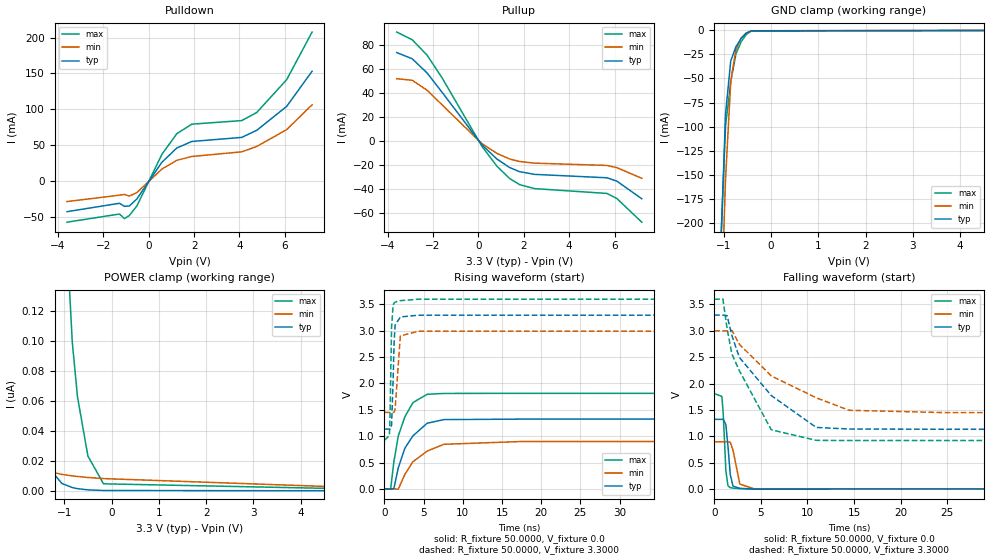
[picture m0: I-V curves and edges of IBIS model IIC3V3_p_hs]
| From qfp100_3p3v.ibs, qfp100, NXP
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[Model] IIC3V3_p_hs
|   Model IIC3V3_p_hs
| This model was characterised for following simulation conditions:
| External (pad) voltage:
|   - Typ: 3.3V,   - Min: 3.0V,   - Max: 3.6V
| Library cells for typ/min/max conditions are connected as defined below:
|  IO - External Pad
|  A - Core Input
|  EN - Output Buffer Enable
|  BOOST - vdde
|  EGP - vdd
|  EHS - vdd
|  ENZI - vdd
|  EPD - gnd
|  EPUN - vdd
|  ZI - NC
|  ZIF - NC
|  gnd - gnd
|  gnde - gnde
|  vdd - vdd
|  vdde - vdde
| All other pins connected to ground
Model_type I/O
Polarity   Non-Inverting
Enable   Active-Low
Vinl =   0.9900V
Vinh =   2.3100V
Vmeas =  1.6500V
Cref =   0.0F
Rref =   1.0000k
Vref =   0.0V
C_comp   3.6227pF   3.4779pF   3.7656pF
|C_comp_pullup   0.9287pF   0.9115pF   0.9356pF
|C_comp_pulldown   2.3426pF   2.4945pF   2.1982pF
[Model Spec]
| variable   typ   min   max
Vinh   0.9900V   0.9000V   1.0800V
Vinl   2.3100V   2.1000V   2.5200V
Vmeas   1.6500V   1.5000V   1.8000V
[Temperature Range]   25.0000   0.1250k   -40.0000
[Voltage Range]   3.3000V   3.0000V   3.6000V
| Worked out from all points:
|   slope of the pulldown table from 0 to 0.495 V, typ, clamps not added: 22 ohm
|   slope of the pullup table from 0 to 0.495 V, typ, clamps not added: 50.2 ohm
|   GND clamp passes 1 mA (typ) near -0.43 V on its own axis
|   rising waveform, R_fixture 50.0000, V_fixture 0.0: 20-80 % time 2.42ns typ, 3.15ns min, 1.81ns max; typ from 0 V to 1.32 V
|   rising waveform, R_fixture 50.0000, V_fixture 3.3000: 20-80 % time 230ps typ, 322ps min, 186ps max; typ from 1.14 V to 3.3 V
|   falling waveform, R_fixture 50.0000, V_fixture 0.0: 20-80 % time 371ps typ, 535ps min, 282ps max; typ from 1.32 V to 0 V
|   falling waveform, R_fixture 50.0000, V_fixture 3.3000: 20-80 % time 5.52ns typ, 7.85ns min, 3.84ns max; typ from 3.3 V to 1.14 V
[Pulldown]
|Voltage   I(typ)   I(min)   I(max)
-3.6V     -43.22mA   -29.09mA   -57.9mA
-1.29V    -31.46mA   -20.15mA   -46.47mA
-1.07V    -35.79mA   -19.19mA   -52.9mA
-850mV    -35.14mA   -21.36mA   -48.43mA
-520mV    -25.35mA   -16.52mA   -35.11mA
580mV     25.81mA    16.3mA     36.8mA
1.24V     45.79mA    28.53mA    65.82mA
1.9V      54.89mA    33.9mA     79.08mA
4.1V      60.56mA    40.39mA    84.05mA
4.76V     70.46mA    47.89mA    95.34mA
6.08V     103.9mA    71.43mA    141.2mA
7.2V      153mA      106.1mA    207.7mA
[Pullup]
|Voltage   I(typ)   I(min)   I(max)
-3.6V     73.7mA     51.87mA    90.79mA
-2.92V    68.56mA    50.58mA    84.45mA
-2.26V    56.64mA    42.24mA    71.49mA
-1.6V     40.55mA    30.05mA    52.55mA
160mV     -3.402mA   -2.371mA   -4.704mA
820mV     -15.2mA    -10.46mA   -21.22mA
1.37V     -22.16mA   -15.02mA   -31.28mA
1.81V     -25.65mA   -17.18mA   -36.45mA
2.47V     -27.92mA   -18.56mA   -39.79mA
5.66V     -30.76mA   -20.47mA   -43.83mA
6.1V      -33.55mA   -22.29mA   -48.04mA
7.2V      -48.27mA   -31.2mA    -67.82mA
[GND_clamp]
|Voltage   I(typ)   I(min)   I(max)
-3.6V     -5.602A    -5.487A    -5.717A
-1.07V    -242mA     -316.8mA   -230.5mA
-960mV    -86.75mA   -154.7mA   -99.48mA
-850mV    -31.81mA   -53.08mA   -53.5mA
-740mV    -16.96mA   -19.87mA   -24.43mA
-630mV    -8.589mA   -7.919mA   -11.88mA
-520mV    -2.996mA   -2.727mA   -4.187mA
-410mV    -432.5uA   -495.8uA   -580.8uA
7.2V      0A         0A         0A
[POWER_clamp]
|Voltage   I(typ)   I(min)   I(max)
-3.6V     2.12uA     118.8nA    63.41uA
-3.03V    844.5nA    61.84nA    27.62uA
-2.37V    225.8nA    29.91nA    8.403uA
-2.04V    102.5nA    21.72nA    4.105uA
-1.82V    57.11nA    17.98nA    2.406uA
-1.49V    21.61nA    14.11nA    975.4nA
-1.05V    4.967nA    11.05nA    231.3nA
-830mV    2.261nA    10.06nA    99.54nA
-720mV    1.525nA    9.658nA    63.01nA
-500mV    718.9pA    8.985nA    23.37nA
-170mV    294.4pA    8.237nA    4.755nA
7.2V      0A         0A         0A
[Ramp]
| variable   typ   min   max
dV/dt_r  0.7941/2.4211n   0.5390/3.1525n   1.0875/1.8120n
dV/dt_f  1.2989/5.5187n   0.9297/7.8507n   1.6070/3.8381n
R_load = 50.0000
[Rising Waveform]
R_fixture= 50.0000
V_fixture= 0.0
V_fixture_min= 0.0
V_fixture_max= 0.0
|time   V(typ)   V(min)   V(max)
0s        2.243nV    52.63nV    27.54nV
783.4ps   -2.546mV   48.23uV    -3.663mV
1.2ns     6.371mV    -1.183mV   516.9mV
1.762ns   400.2mV    -5.572mV   1.005V
2.604ns   772.3mV    274.8mV    1.368V
3.633ns   1.006V     515.9mV    1.636V
5.446ns   1.245V     716.8mV    1.794V
7.589ns   1.314V     845.6mV    1.81V
17.45ns   1.323V     898mV      1.812V
1us       1.323V     898.3mV    1.813V
[Rising Waveform]
R_fixture= 50.0000
V_fixture= 3.3000
V_fixture_min= 3.0000
V_fixture_max= 3.6000
|time   V(typ)   V(min)   V(max)
0s        1.135V     1.45V      921.7mV
627.3ps   1.135V     1.45V      1.012V
700.7ps   1.134V     1.451V     1.326V
903.6ps   1.208V     1.45V      3.068V
1.101ns   2.057V     1.448V     3.484V
1.223ns   2.763V     1.454V     3.525V
1.356ns   3.105V     1.506V     3.542V
2.023ns   3.26V      2.9V       3.57V
4.301ns   3.294V     2.99V      3.597V
1us       3.3V       3V         3.6V
[Falling Waveform]
R_fixture= 50.0000
V_fixture= 0.0
V_fixture_min= 0.0
V_fixture_max= 0.0
|time   V(typ)   V(min)   V(max)
0s        1.323V     898.3mV    1.813V
822ps     1.323V     898.3mV    1.758V
972.4ps   1.326V     898.3mV    1.431V
1.252ns   1.222V     898.1mV    350.6mV
1.476ns   816.9mV    900.3mV    64.93mV
1.726ns   277.3mV    889.4mV    27.64mV
2.019ns   57.27mV    737.3mV    19.74mV
2.754ns   14.85mV    95.71mV    10.98mV
4.273ns   3.379mV    7.479mV    1.748mV
1us       13.95nV    73.04nV    34.74nV
[Falling Waveform]
R_fixture= 50.0000
V_fixture= 3.3000
V_fixture_min= 3.0000
V_fixture_max= 3.6000
|time   V(typ)   V(min)   V(max)
0s        3.3V       3V         3.6V
933.7ps   3.299V     3V         3.603V
1.389ns   3.287V     2.999V     3.037V
1.891ns   2.917V     3.01V      2.567V
2.697ns   2.498V     2.747V     2.246V
6.123ns   1.774V     2.146V     1.125V
10.95ns   1.17V      1.732V     925.1mV
14.46ns   1.14V      1.495V     922mV
24.74ns   1.135V     1.451V     921.7mV
1us       1.135V     1.45V      921.7mV
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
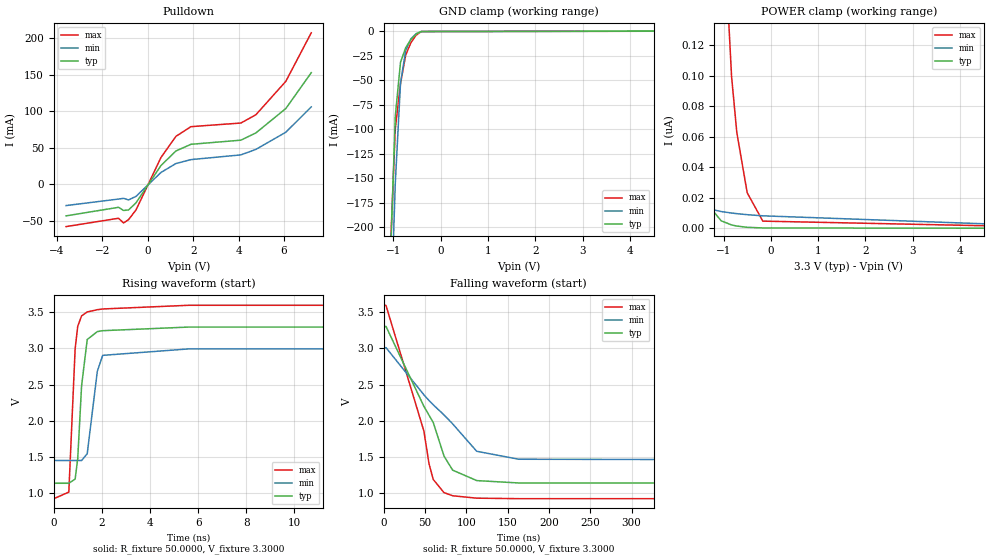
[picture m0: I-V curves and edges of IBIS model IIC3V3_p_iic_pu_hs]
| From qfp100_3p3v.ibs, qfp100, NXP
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[Model] IIC3V3_p_iic_pu_hs
|   Model IIC3V3_p_iic_pu_hs
| This model was characterised for following simulation conditions:
| External (pad) voltage:
|   - Typ: 3.3V,   - Min: 3.0V,   - Max: 3.6V
| Library cells for typ/min/max conditions are connected as defined below:
|  IO - External Pad
|  A - Core Input
|  EN - Output Buffer Enable
|  BOOST - vdde
|  ECS - vdd
|  EGP - gnd
|  ENZI - vdd
|  EPD - gnd
|  EPUN - vdd
|  SSEL - vdd
|  ZI - NC
|  ZIF - NC
|  gnd - gnd
|  gnde - gnde
|  vdd - vdd
|  vdde - vdde
| All other pins connected to ground
Model_type I/O_open_drain
Polarity   Non-Inverting
Enable   Active-Low
Vinl =   0.9900V
Vinh =   2.3100V
Vmeas =  1.6500V
Cref =   0.0F
Rref =   1.0000k
Vref =   3.3000V
C_comp   3.6227pF   3.4779pF   3.7656pF
|C_comp_pullup   0.9287pF   0.9114pF   0.9356pF
|C_comp_pulldown   2.3426pF   2.4946pF   2.1982pF
[Model Spec]
| variable   typ   min   max
Vinh   0.9900V   0.9000V   1.0800V
Vinl   2.3100V   2.1000V   2.5200V
Vmeas   1.6500V   1.5000V   1.8000V
Vref   3.3000V   3.0000V   3.6000V
Cref   0.0F   0.0F   0.0F
Rref   1.0000k   1.0000k   1.0000k
[Temperature Range]   25.0000   0.1250k   -40.0000
[Voltage Range]   3.3000V   3.0000V   3.6000V
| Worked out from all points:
|   slope of the pulldown table from 0 to 0.495 V, typ, clamps not added: 22 ohm
|   GND clamp passes 1 mA (typ) near -0.43 V on its own axis
|   rising waveform, R_fixture 50.0000, V_fixture 3.3000: 20-80 % time 227ps typ, 309ps min, 192ps max; typ from 1.14 V to 3.3 V
|   falling waveform, R_fixture 50.0000, V_fixture 3.3000: 20-80 % time 50.8ns typ, 68.7ns min, 38.5ns max; typ from 3.3 V to 1.14 V
[Pulldown]
|Voltage   I(typ)   I(min)   I(max)
-3.6V     -43.22mA   -29.09mA   -57.9mA
-1.29V    -31.46mA   -20.15mA   -46.47mA
-1.07V    -35.79mA   -19.19mA   -52.9mA
-850mV    -35.14mA   -21.36mA   -48.43mA
-520mV    -25.35mA   -16.52mA   -35.11mA
580mV     25.81mA    16.3mA     36.8mA
1.24V     45.79mA    28.53mA    65.82mA
1.9V      54.89mA    33.9mA     79.08mA
4.1V      60.56mA    40.39mA    84.05mA
4.76V     70.46mA    47.89mA    95.34mA
6.08V     103.9mA    71.43mA    141.2mA
7.2V      153mA      106.1mA    207.7mA
[GND_clamp]
|Voltage   I(typ)   I(min)   I(max)
-3.6V     -5.602A    -5.487A    -5.717A
-1.07V    -242mA     -316.8mA   -230.5mA
-960mV    -86.75mA   -154.7mA   -99.48mA
-850mV    -31.81mA   -53.08mA   -53.5mA
-740mV    -16.96mA   -19.87mA   -24.43mA
-630mV    -8.589mA   -7.919mA   -11.88mA
-520mV    -2.996mA   -2.727mA   -4.187mA
-410mV    -432.5uA   -495.8uA   -580.8uA
7.2V      0A         0A         0A
[POWER_clamp]
|Voltage   I(typ)   I(min)   I(max)
-3.6V     2.12uA     118.8nA    63.41uA
-3.03V    844.5nA    61.84nA    27.62uA
-2.37V    225.8nA    29.91nA    8.403uA
-2.04V    102.5nA    21.72nA    4.105uA
-1.82V    57.11nA    17.98nA    2.406uA
-1.49V    21.61nA    14.11nA    975.4nA
-1.05V    4.967nA    11.05nA    231.3nA
-830mV    2.261nA    10.06nA    99.54nA
-720mV    1.525nA    9.658nA    63.01nA
-500mV    718.9pA    8.985nA    23.37nA
-170mV    294.4pA    8.237nA    4.755nA
7.2V      0A         0A         0A
[Ramp]
| variable   typ   min   max
dV/dt_r  1.2989/0.2271n   0.9297/0.3090n   1.6070/0.1925n
dV/dt_f  1.2989/50.7796n   0.9297/68.6526n   1.6070/38.5019n
R_load = 50.0000
[Rising Waveform]
R_fixture= 50.0000
V_fixture= 3.3000
V_fixture_min= 3.0000
V_fixture_max= 3.6000
|time   V(typ)   V(min)   V(max)
0s        1.135V     1.45V      921.7mV
623.4ps   1.135V     1.45V      1.013V
886ps     1.193V     1.45V      2.995V
994ps     1.479V     1.45V      3.305V
1.153ns   2.48V      1.449V     3.448V
1.388ns   3.122V     1.544V     3.503V
1.807ns   3.231V     2.682V     3.534V
2.03ns    3.244V     2.903V     3.544V
5.603ns   3.294V     2.992V     3.595V
1us       3.3V       3V         3.6V
[Falling Waveform]
R_fixture= 50.0000
V_fixture= 3.3000
V_fixture_min= 3.0000
V_fixture_max= 3.6000
|time   V(typ)   V(min)   V(max)
0s        3.3V       3V         3.6V
2.46ns    3.303V     3.01V      3.593V
48.38ns   2.199V     2.358V     1.857V
54.58ns   2.076V     2.28V      1.407V
59.71ns   1.976V     2.22V      1.188V
72.76ns   1.512V     2.08V      1.006V
83.18ns   1.317V     1.957V     962.6mV
112.4ns   1.172V     1.577V     928.9mV
163.4ns   1.139V     1.467V     922.1mV
1us       1.135V     1.45V      921.7mV
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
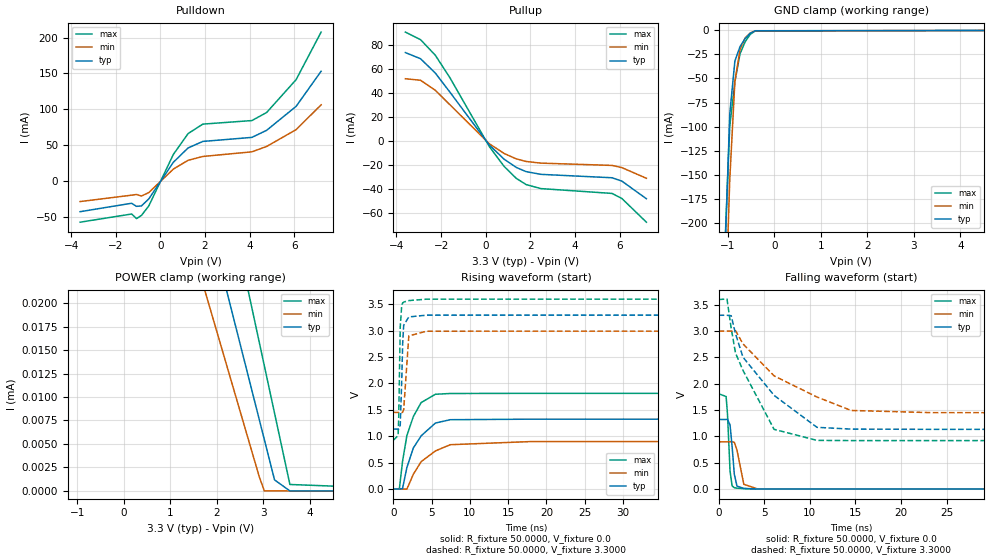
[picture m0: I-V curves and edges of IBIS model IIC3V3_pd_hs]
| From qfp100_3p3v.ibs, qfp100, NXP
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[Model] IIC3V3_pd_hs
|   Model IIC3V3_pd_hs
| This model was characterised for following simulation conditions:
| External (pad) voltage:
|   - Typ: 3.3V,   - Min: 3.0V,   - Max: 3.6V
| Library cells for typ/min/max conditions are connected as defined below:
|  IO - External Pad
|  A - Core Input
|  EN - Output Buffer Enable
|  BOOST - vdde
|  EGP - vdd
|  EHS - vdd
|  ENZI - vdd
|  EPD - vdd
|  EPUN - vdd
|  ZI - NC
|  ZIF - NC
|  gnd - gnd
|  gnde - gnde
|  vdd - vdd
|  vdde - vdde
| All other pins connected to ground
Model_type I/O
Polarity   Non-Inverting
Enable   Active-Low
Vinl =   0.9900V
Vinh =   2.3100V
Vmeas =  1.6500V
Cref =   0.0F
Rref =   1.0000k
Vref =   0.0V
C_comp   3.5907pF   3.4406pF   3.7387pF
|C_comp_pullup   0.9138pF   0.9000pF   0.9174pF
|C_comp_pulldown   2.3267pF   2.4802pF   2.1806pF
[Model Spec]
| variable   typ   min   max
Vinh   0.9900V   0.9000V   1.0800V
Vinl   2.3100V   2.1000V   2.5200V
Vmeas   1.6500V   1.5000V   1.8000V
[Temperature Range]   25.0000   0.1250k   -40.0000
[Voltage Range]   3.3000V   3.0000V   3.6000V
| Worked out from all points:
|   slope of the pulldown table from 0 to 0.495 V, typ, clamps not added: 22 ohm
|   slope of the pullup table from 0 to 0.495 V, typ, clamps not added: 50.2 ohm
|   GND clamp passes 1 mA (typ) near -0.43 V on its own axis
|   rising waveform, R_fixture 50.0000, V_fixture 0.0: 20-80 % time 2.41ns typ, 3.15ns min, 1.81ns max; typ from 0 V to 1.32 V
|   rising waveform, R_fixture 50.0000, V_fixture 3.3000: 20-80 % time 230ps typ, 322ps min, 186ps max; typ from 1.14 V to 3.3 V
|   falling waveform, R_fixture 50.0000, V_fixture 0.0: 20-80 % time 371ps typ, 533ps min, 281ps max; typ from 1.32 V to 0 V
|   falling waveform, R_fixture 50.0000, V_fixture 3.3000: 20-80 % time 5.51ns typ, 7.83ns min, 3.82ns max; typ from 3.3 V to 1.14 V
[Pulldown]
|Voltage   I(typ)   I(min)   I(max)
-3.6V     -43.22mA   -29.09mA   -57.9mA
-1.29V    -31.46mA   -20.15mA   -46.47mA
-1.07V    -35.79mA   -19.19mA   -52.9mA
-850mV    -35.14mA   -21.36mA   -48.43mA
-520mV    -25.35mA   -16.52mA   -35.11mA
580mV     25.81mA    16.3mA     36.8mA
1.24V     45.79mA    28.53mA    65.82mA
1.9V      54.89mA    33.9mA     79.08mA
4.1V      60.55mA    40.38mA    84.05mA
4.76V     70.44mA    47.87mA    95.32mA
6.08V     103.9mA    71.39mA    141.2mA
7.2V      152.9mA    106mA      207.6mA
[Pullup]
|Voltage   I(typ)   I(min)   I(max)
-3.6V     73.65mA    51.83mA    90.73mA
-2.92V    68.52mA    50.55mA    84.41mA
-2.26V    56.61mA    42.22mA    71.46mA
-1.6V     40.53mA    30.04mA    52.53mA
160mV     -3.403mA   -2.371mA   -4.704mA
820mV     -15.2mA    -10.46mA   -21.22mA
1.37V     -22.16mA   -15.02mA   -31.28mA
1.81V     -25.65mA   -17.18mA   -36.45mA
2.47V     -27.92mA   -18.56mA   -39.79mA
5.66V     -30.76mA   -20.47mA   -43.83mA
6.1V      -33.55mA   -22.29mA   -48.04mA
7.2V      -48.27mA   -31.2mA    -67.82mA
[GND_clamp]
|Voltage   I(typ)   I(min)   I(max)
-3.6V     -5.602A    -5.487A    -5.717A
-1.07V    -242mA     -316.8mA   -230.5mA
-960mV    -86.76mA   -154.7mA   -99.49mA
-850mV    -31.82mA   -53.09mA   -53.51mA
-740mV    -16.97mA   -19.87mA   -24.44mA
-630mV    -8.597mA   -7.926mA   -11.89mA
-520mV    -3.004mA   -2.733mA   -4.196mA
-410mV    -439.7uA   -501.8uA   -589.4uA
7.2V      0A         0A         0A
[POWER_clamp]
|Voltage   I(typ)   I(min)   I(max)
-3.6V     137uA      111.9uA    228.9uA
-3.47V    134.1uA    109.7uA    215.6uA
-3.25V    129.3uA    106uA      196.2uA
-2.92V    122.3uA    100.4uA    172.9uA
-2.48V    113.3uA    92.88uA    150.2uA
-2.04V    104.5uA    85.42uA    133.7uA
-1.16V    87.2uA     70.51uA    109.7uA
2.91V     7.626uA    1.527uA    15.86uA
3.02V     5.475uA    0A         13.33uA
3.24V     1.173uA    0A         8.273uA
3.57V     0A         0A         687.1nA
7.2V      0A         0A         0A
[Ramp]
| variable   typ   min   max
dV/dt_r  0.7935/2.4144n   0.5386/3.1478n   1.0867/1.8089n
dV/dt_f  1.2983/5.5124n   0.9293/7.8350n   1.6062/3.8243n
R_load = 50.0000
[Rising Waveform]
R_fixture= 50.0000
V_fixture= 0.0
V_fixture_min= 0.0
V_fixture_max= 0.0
|time   V(typ)   V(min)   V(max)
0s        2.145nV    50.58nV    26.14nV
784.7ps   -2.611mV   49.1uV     -3.137mV
1.202ns   7.028mV    -1.221mV   519mV
1.771ns   405.7mV    -4.318mV   1.01V
2.618ns   776.7mV    279.1mV    1.373V
3.639ns   1.007V     517.2mV    1.637V
5.503ns   1.249V     720.8mV    1.794V
7.438ns   1.312V     838.3mV    1.809V
17.91ns   1.322V     897.4mV    1.811V
1us       1.322V     897.6mV    1.811V
[Rising Waveform]
R_fixture= 50.0000
V_fixture= 3.3000
V_fixture_min= 3.0000
V_fixture_max= 3.6000
|time   V(typ)   V(min)   V(max)
0s        1.135V     1.45V      921.3mV
628ps     1.134V     1.45V      1.013V
701.4ps   1.133V     1.45V      1.33V
904.8ps   1.209V     1.449V     3.073V
1.102ns   2.066V     1.447V     3.485V
1.223ns   2.761V     1.453V     3.525V
1.356ns   3.104V     1.505V     3.541V
2.025ns   3.259V     2.9V       3.569V
4.329ns   3.293V     2.989V     3.596V
1us       3.299V     2.999V     3.598V
[Falling Waveform]
R_fixture= 50.0000
V_fixture= 0.0
V_fixture_min= 0.0
V_fixture_max= 0.0
|time   V(typ)   V(min)   V(max)
0s        1.322V     897.6mV    1.811V
823ps     1.322V     897.6mV    1.756V
974.3ps   1.325V     897.6mV    1.423V
1.254ns   1.218V     897.5mV    343.4mV
1.479ns   809.6mV    899.6mV    62.93mV
1.72ns    284.1mV    889.7mV    27.16mV
2.013ns   58.28mV    741.7mV    19.25mV
2.763ns   14.33mV    92.17mV    10.48mV
4.222ns   3.365mV    7.6mV      1.686mV
1us       13.83nV    70.96nV    33.33nV
[Falling Waveform]
R_fixture= 50.0000
V_fixture= 3.3000
V_fixture_min= 3.0000
V_fixture_max= 3.6000
|time   V(typ)   V(min)   V(max)
0s        3.299V     2.999V     3.598V
922.2ps   3.298V     2.999V     3.606V
1.378ns   3.29V      2.998V     3.054V
1.853ns   2.949V     3.007V     2.582V
2.668ns   2.504V     2.757V     2.255V
6.08ns    1.779V     2.149V     1.135V
10.78ns   1.173V     1.748V     925.2mV
14.53ns   1.139V     1.493V     921.7mV
23.45ns   1.135V     1.451V     921.4mV
1us       1.135V     1.45V      921.3mV
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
